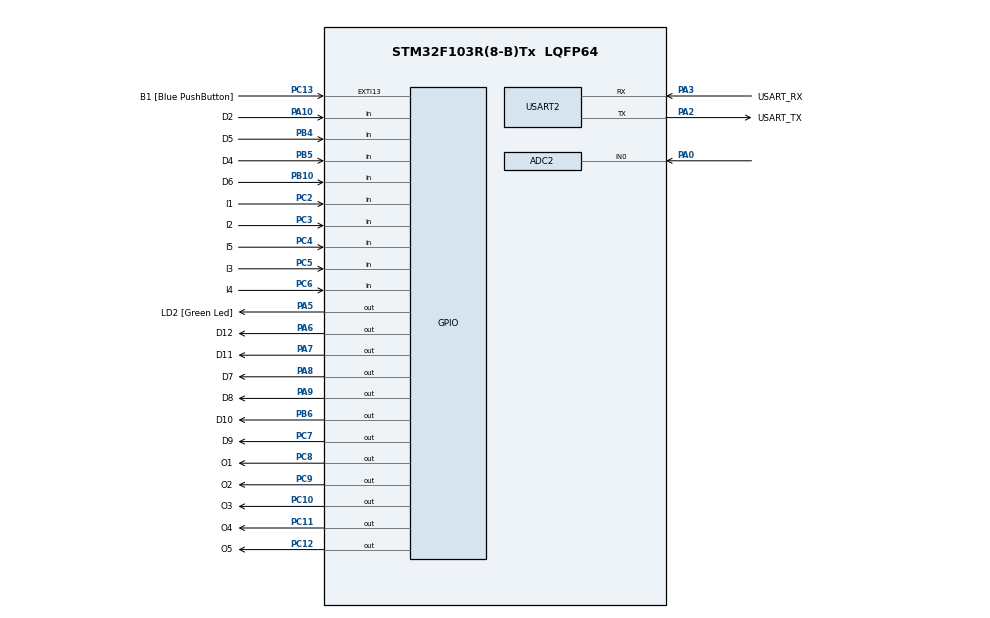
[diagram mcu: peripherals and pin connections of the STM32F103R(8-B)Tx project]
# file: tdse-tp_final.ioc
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ADC1.Channel-0\#ChannelRegularConversion=ADC_CHANNEL_TEMPSENSOR
ADC1.EnableAnalogWatchDog=false
ADC1.NbrOfConversion=1
ADC1.NbrOfConversionFlag=1
ADC1.Rank-0\#ChannelRegularConversion=1
ADC1.SamplingTime-0\#ChannelRegularConversion=ADC_SAMPLETIME_71CYCLES_5
ADC1.master=1
ADC2.Channel-1\#ChannelRegularConversion=ADC_CHANNEL_0
ADC2.NbrOfConversionFlag=1
ADC2.Rank-1\#ChannelRegularConversion=1
ADC2.SamplingTime-1\#ChannelRegularConversion=ADC_SAMPLETIME_71CYCLES_5
Mcu.Family=STM32F1
Mcu.Name=STM32F103R(8-B)Tx
Mcu.Package=LQFP64
NVIC.ADC1_2_IRQn=true\:0\:0\:false\:false\:true\:true\:true\:true
NVIC.EXTI15_10_IRQn=true\:0\:0\:false\:false\:true\:true\:true\:true
NVIC.PriorityGroup=NVIC_PRIORITYGROUP_4
PA0-WKUP.Signal=ADCx_IN0
PA10.GPIO_Label=D2
PA10.GPIO_PuPd=GPIO_PULLUP
PA10.Signal=GPIO_Input
PA13.GPIO_Label=TMS
PA13.Mode=Serial_Wire
PA13.Signal=SYS_JTMS-SWDIO
PA14.GPIO_Label=TCK
PA14.Mode=Serial_Wire
PA14.Signal=SYS_JTCK-SWCLK
PA2.GPIO_Label=USART_TX
PA2.GPIO_Mode=GPIO_MODE_AF_PP
PA2.GPIO_PuPd=GPIO_NOPULL
PA2.GPIO_Speed=GPIO_SPEED_FREQ_LOW
PA2.Mode=Asynchronous
PA2.Signal=USART2_TX
PA3.GPIO_Label=USART_RX
PA3.GPIO_Mode=GPIO_MODE_AF_PP
PA3.GPIO_PuPd=GPIO_NOPULL
PA3.GPIO_Speed=GPIO_SPEED_FREQ_LOW
PA3.Mode=Asynchronous
PA3.Signal=USART2_RX
PA5.GPIO_Label=LD2 [Green Led]
PA5.GPIO_ModeDefaultOutputPP=GPIO_MODE_OUTPUT_PP
PA5.GPIO_PuPd=GPIO_NOPULL
PA5.GPIO_Speed=GPIO_SPEED_FREQ_LOW
PA5.Signal=GPIO_Output
PA6.GPIO_Label=D12
PA6.Signal=GPIO_Output
PA7.GPIO_Label=D11
PA7.Signal=GPIO_Output
PA8.GPIO_Label=D7
PA8.Signal=GPIO_Output
PA9.GPIO_Label=D8
PA9.Signal=GPIO_Output
PB10.GPIO_Label=D6
PB10.GPIO_PuPd=GPIO_PULLUP
PB10.Signal=GPIO_Input
PB3.GPIO_Label=SWO
PB3.Signal=SYS_JTDO-TRACESWO
PB4.GPIO_Label=D5
PB4.GPIO_PuPd=GPIO_PULLUP
PB4.Signal=GPIO_Input
PB5.GPIO_Label=D4
PB5.GPIO_PuPd=GPIO_PULLUP
PB5.Signal=GPIO_Input
PB6.GPIO_Label=D10
PB6.Signal=GPIO_Output
PC10.GPIO_Label=O3
PC10.Signal=GPIO_Output
PC11.GPIO_Label=O4
PC11.Signal=GPIO_Output
PC12.GPIO_Label=O5
PC12.PinState=GPIO_PIN_SET
PC12.Signal=GPIO_Output
PC13-TAMPER-RTC.GPIO_Label=B1 [Blue PushButton]
PC13-TAMPER-RTC.GPIO_ModeDefaultEXTI=GPIO_MODE_IT_RISING
PC13-TAMPER-RTC.GPIO_PuPd=GPIO_NOPULL
PC13-TAMPER-RTC.Signal=GPXTI13
PC14-OSC32_IN.Mode=LSE-External-Oscillator
PC14-OSC32_IN.Signal=RCC_OSC32_IN
PC15-OSC32_OUT.Mode=LSE-External-Oscillator
PC15-OSC32_OUT.Signal=RCC_OSC32_OUT
PC2.GPIO_Label=I1
PC2.GPIO_PuPd=GPIO_PULLUP
PC2.Signal=GPIO_Input
PC3.GPIO_Label=I2
PC3.GPIO_PuPd=GPIO_PULLUP
PC3.Signal=GPIO_Input
PC4.GPIO_Label=I5
PC4.GPIO_PuPd=GPIO_PULLUP
PC4.Signal=GPIO_Input
PC5.GPIO_Label=I3
PC5.GPIO_PuPd=GPIO_PULLUP
PC5.Signal=GPIO_Input
PC6.GPIO_Label=I4
PC6.GPIO_PuPd=GPIO_PULLUP
PC6.Signal=GPIO_Input
PC7.GPIO_Label=D9
PC7.Signal=GPIO_Output
PC8.GPIO_Label=O1
PC8.Signal=GPIO_Output
PC9.GPIO_Label=O2
PC9.Signal=GPIO_Output
PD0-OSC_IN.Mode=HSE-External-Clock-Source
PD0-OSC_IN.Signal=RCC_OSC_IN
PD1-OSC_OUT.Mode=HSE-External-Clock-Source
PD1-OSC_OUT.Signal=RCC_OSC_OUT
ProjectManager.HeapSize=0x200
ProjectManager.StackSize=0x400
ProjectManager.TargetToolchain=STM32CubeIDE
RCC.ADCPresc=RCC_ADCPCLK2_DIV8
RCC.AHBFreq_Value=64000000
RCC.APB1CLKDivider=RCC_HCLK_DIV2
RCC.APB1Freq_Value=32000000
RCC.APB1TimFreq_Value=64000000
RCC.APB2Freq_Value=64000000
RCC.APB2TimFreq_Value=64000000
RCC.HCLKFreq_Value=64000000
RCC.PLLMUL=RCC_PLL_MUL16
RCC.RTCClockSelection=RCC_RTCCLKSOURCE_LSE
RCC.SYSCLKFreq_VALUE=64000000
RCC.SYSCLKSource=RCC_SYSCLKSOURCE_PLLCLK
RCC.USBFreq_Value=64000000
SH.ADCx_IN0.0=ADC1_IN0
SH.ADCx_IN0.1=ADC2_IN0,IN0
USART2.VirtualMode=VM_ASYNC
VP_ADC1_TempSens_Input.Mode=IN-TempSens
board=NUCLEO-F103RB

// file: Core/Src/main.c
/* USER CODE BEGIN Header */
/**
  ******************************************************************************
  * @file           : main.c
  * @brief          : Main program body
  ******************************************************************************
  * @attention
  *
  * <h2><center>&copy; Copyright (c) 2024 STMicroelectronics.
  * All rights reserved.</center></h2>
  *
  * This software component is licensed by ST under BSD 3-Clause license,
  * the "License"; You may not use this file except in compliance with the
  * License. You may obtain a copy of the License at:
  *                        opensource.org/licenses/BSD-3-Clause
  *
  ******************************************************************************
  */
/* USER CODE END Header */
#include "main.h"

/* USER CODE BEGIN Includes */

/* Demo includes. */
#include "logger.h"
#include "dwt.h"

/* Application includes. */
#include "app.h"

/* USER CODE END Includes */

ADC_HandleTypeDef hadc1;
ADC_HandleTypeDef hadc2;

UART_HandleTypeDef huart2;

void SystemClock_Config(void);
static void MX_GPIO_Init(void);
static void MX_USART2_UART_Init(void);
static void MX_ADC1_Init(void);
static void MX_ADC2_Init(void);

/* USER CODE BEGIN 0 */
extern void initialise_monitor_handles(void);

/* USER CODE END 0 */

int main(void)
{

  /* USER CODE BEGIN 1 */
	initialise_monitor_handles();

  /* USER CODE END 1 */

  /* MCU Configuration--------------------------------------------------------*/

  /* Reset of all peripherals, Initializes the Flash interface and the Systick. */
  HAL_Init();

  /* Configure the system clock */
  SystemClock_Config();

  /* Initialize all configured peripherals */
  MX_GPIO_Init();
  MX_USART2_UART_Init();
  MX_ADC1_Init();
  MX_ADC2_Init();
  /* USER CODE BEGIN 2 */

	/* Application Init */
  app_init();

  /* USER CODE END 2 */

  /* Infinite loop */
  while (1)
  {

    /* USER CODE BEGIN 3 */

	  /* Application Update */
	  app_update();
  }
  /* USER CODE END 3 */
}

void SystemClock_Config(void)
{
  RCC_OscInitTypeDef RCC_OscInitStruct = {0};
  RCC_ClkInitTypeDef RCC_ClkInitStruct = {0};
  RCC_PeriphCLKInitTypeDef PeriphClkInit = {0};

  /** Initializes the RCC Oscillators according to the specified parameters
  * in the RCC_OscInitTypeDef structure.
  */
  RCC_OscInitStruct.OscillatorType = RCC_OSCILLATORTYPE_HSI;
  RCC_OscInitStruct.HSIState = RCC_HSI_ON;
  RCC_OscInitStruct.HSICalibrationValue = RCC_HSICALIBRATION_DEFAULT;
  RCC_OscInitStruct.PLL.PLLState = RCC_PLL_ON;
  RCC_OscInitStruct.PLL.PLLSource = RCC_PLLSOURCE_HSI_DIV2;
  RCC_OscInitStruct.PLL.PLLMUL = RCC_PLL_MUL16;
  if (HAL_RCC_OscConfig(&RCC_OscInitStruct) != HAL_OK)
  {
    Error_Handler();
  }

  /** Initializes the CPU, AHB and APB buses clocks
  */
  RCC_ClkInitStruct.ClockType = RCC_CLOCKTYPE_HCLK|RCC_CLOCKTYPE_SYSCLK
                              |RCC_CLOCKTYPE_PCLK1|RCC_CLOCKTYPE_PCLK2;
  RCC_ClkInitStruct.SYSCLKSource = RCC_SYSCLKSOURCE_PLLCLK;
  RCC_ClkInitStruct.AHBCLKDivider = RCC_SYSCLK_DIV1;
  RCC_ClkInitStruct.APB1CLKDivider = RCC_HCLK_DIV2;
  RCC_ClkInitStruct.APB2CLKDivider = RCC_HCLK_DIV16;

  if (HAL_RCC_ClockConfig(&RCC_ClkInitStruct, FLASH_LATENCY_2) != HAL_OK)
  {
    Error_Handler();
  }
  PeriphClkInit.PeriphClockSelection = RCC_PERIPHCLK_ADC;
  PeriphClkInit.AdcClockSelection = RCC_ADCPCLK2_DIV8;
  if (HAL_RCCEx_PeriphCLKConfig(&PeriphClkInit) != HAL_OK)
  {
    Error_Handler();
  }
}

static void MX_ADC1_Init(void)
{

  ADC_ChannelConfTypeDef sConfig = {0};

  /** Common config
  */
  hadc1.Instance = ADC1;
  hadc1.Init.ScanConvMode = ADC_SCAN_DISABLE;
  hadc1.Init.ContinuousConvMode = DISABLE;
  hadc1.Init.DiscontinuousConvMode = DISABLE;
  hadc1.Init.ExternalTrigConv = ADC_SOFTWARE_START;
  hadc1.Init.DataAlign = ADC_DATAALIGN_RIGHT;
  hadc1.Init.NbrOfConversion = 1;
  if (HAL_ADC_Init(&hadc1) != HAL_OK)
  {
    Error_Handler();
  }

  /** Configure Regular Channel
  */
  sConfig.Channel = ADC_CHANNEL_TEMPSENSOR;
  sConfig.Rank = ADC_REGULAR_RANK_1;
  sConfig.SamplingTime = ADC_SAMPLETIME_71CYCLES_5;
  if (HAL_ADC_ConfigChannel(&hadc1, &sConfig) != HAL_OK)
  {
    Error_Handler();
  }

}

static void MX_ADC2_Init(void)
{

  ADC_ChannelConfTypeDef sConfig = {0};

  /** Common config
  */
  hadc2.Instance = ADC2;
  hadc2.Init.ScanConvMode = ADC_SCAN_DISABLE;
  hadc2.Init.ContinuousConvMode = DISABLE;
  hadc2.Init.DiscontinuousConvMode = DISABLE;
  hadc2.Init.ExternalTrigConv = ADC_SOFTWARE_START;
  hadc2.Init.DataAlign = ADC_DATAALIGN_RIGHT;
  hadc2.Init.NbrOfConversion = 1;
  if (HAL_ADC_Init(&hadc2) != HAL_OK)
  {
    Error_Handler();
  }

  /** Configure Regular Channel
  */
  sConfig.Channel = ADC_CHANNEL_0;
  sConfig.Rank = ADC_REGULAR_RANK_1;
  sConfig.SamplingTime = ADC_SAMPLETIME_71CYCLES_5;
  if (HAL_ADC_ConfigChannel(&hadc2, &sConfig) != HAL_OK)
  {
    Error_Handler();
  }

}

static void MX_USART2_UART_Init(void)
{

  huart2.Instance = USART2;
  huart2.Init.BaudRate = 115200;
  huart2.Init.WordLength = UART_WORDLENGTH_8B;
  huart2.Init.StopBits = UART_STOPBITS_1;
  huart2.Init.Parity = UART_PARITY_NONE;
  huart2.Init.Mode = UART_MODE_TX_RX;
  huart2.Init.HwFlowCtl = UART_HWCONTROL_NONE;
  huart2.Init.OverSampling = UART_OVERSAMPLING_16;
  if (HAL_UART_Init(&huart2) != HAL_OK)
  {
    Error_Handler();
  }

}

static void MX_GPIO_Init(void)
{
  GPIO_InitTypeDef GPIO_InitStruct = {0};

  /* GPIO Ports Clock Enable */
  __HAL_RCC_GPIOC_CLK_ENABLE();
  __HAL_RCC_GPIOD_CLK_ENABLE();
  __HAL_RCC_GPIOA_CLK_ENABLE();
  __HAL_RCC_GPIOB_CLK_ENABLE();

  /*Configure GPIO pin Output Level */
  HAL_GPIO_WritePin(GPIOA, LD2_Pin|D12_Pin|D11_Pin|D7_Pin
                          |D8_Pin, GPIO_PIN_RESET);

  /*Configure GPIO pin Output Level */
  HAL_GPIO_WritePin(GPIOC, D9_Pin|O1_Pin|O2_Pin|O3_Pin
                          |O4_Pin, GPIO_PIN_RESET);

  /*Configure GPIO pin Output Level */
  HAL_GPIO_WritePin(O5_GPIO_Port, O5_Pin, GPIO_PIN_SET);

  /*Configure GPIO pin Output Level */
  HAL_GPIO_WritePin(D10_GPIO_Port, D10_Pin, GPIO_PIN_RESET);

  /*Configure GPIO pin : B1_Pin */
  GPIO_InitStruct.Pin = B1_Pin;
  GPIO_InitStruct.Mode = GPIO_MODE_IT_RISING;
  GPIO_InitStruct.Pull = GPIO_NOPULL;
  HAL_GPIO_Init(B1_GPIO_Port, &GPIO_InitStruct);

  /*Configure GPIO pins : I1_Pin I2_Pin I5_Pin I3_Pin
                           I4_Pin */
  GPIO_InitStruct.Pin = I1_Pin|I2_Pin|I5_Pin|I3_Pin
                          |I4_Pin;
  GPIO_InitStruct.Mode = GPIO_MODE_INPUT;
  GPIO_InitStruct.Pull = GPIO_PULLUP;
  HAL_GPIO_Init(GPIOC, &GPIO_InitStruct);

  /*Configure GPIO pins : LD2_Pin D12_Pin D11_Pin D7_Pin
                           D8_Pin */
  GPIO_InitStruct.Pin = LD2_Pin|D12_Pin|D11_Pin|D7_Pin
                          |D8_Pin;
  GPIO_InitStruct.Mode = GPIO_MODE_OUTPUT_PP;
  GPIO_InitStruct.Pull = GPIO_NOPULL;
  GPIO_InitStruct.Speed = GPIO_SPEED_FREQ_LOW;
  HAL_GPIO_Init(GPIOA, &GPIO_InitStruct);

  /*Configure GPIO pins : D6_Pin D5_Pin D4_Pin */
  GPIO_InitStruct.Pin = D6_Pin|D5_Pin|D4_Pin;
  GPIO_InitStruct.Mode = GPIO_MODE_INPUT;
  GPIO_InitStruct.Pull = GPIO_PULLUP;
  HAL_GPIO_Init(GPIOB, &GPIO_InitStruct);

  /*Configure GPIO pins : D9_Pin O1_Pin O2_Pin O3_Pin
                           O4_Pin O5_Pin */
  GPIO_InitStruct.Pin = D9_Pin|O1_Pin|O2_Pin|O3_Pin
                          |O4_Pin|O5_Pin;
  GPIO_InitStruct.Mode = GPIO_MODE_OUTPUT_PP;
  GPIO_InitStruct.Pull = GPIO_NOPULL;
  GPIO_InitStruct.Speed = GPIO_SPEED_FREQ_LOW;
  HAL_GPIO_Init(GPIOC, &GPIO_InitStruct);

  /*Configure GPIO pin : D2_Pin */
  GPIO_InitStruct.Pin = D2_Pin;
  GPIO_InitStruct.Mode = GPIO_MODE_INPUT;
  GPIO_InitStruct.Pull = GPIO_PULLUP;
  HAL_GPIO_Init(D2_GPIO_Port, &GPIO_InitStruct);

  /*Configure GPIO pin : D10_Pin */
  GPIO_InitStruct.Pin = D10_Pin;
  GPIO_InitStruct.Mode = GPIO_MODE_OUTPUT_PP;
  GPIO_InitStruct.Pull = GPIO_NOPULL;
  GPIO_InitStruct.Speed = GPIO_SPEED_FREQ_LOW;
  HAL_GPIO_Init(D10_GPIO_Port, &GPIO_InitStruct);

  /* EXTI interrupt init*/
  HAL_NVIC_SetPriority(EXTI15_10_IRQn, 0, 0);
  HAL_NVIC_EnableIRQ(EXTI15_10_IRQn);

/* USER CODE BEGIN MX_GPIO_Init_2 */
  HAL_GPIO_WritePin(O5_GPIO_Port, O5_Pin, GPIO_PIN_SET);
/* USER CODE END MX_GPIO_Init_2 */
}

void Error_Handler(void)
{
  __disable_irq();
  while (1)
  {
  }
}
